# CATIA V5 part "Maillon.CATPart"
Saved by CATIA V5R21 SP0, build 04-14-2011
Part number: 0_274m_e14_1_028_0_12
Bounding box of the stored display mesh (mm): x -173.117 to -118.111, y -6 to 21, z 39.524 to 68.389
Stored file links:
  C:\TPO v2\SharedFS\Outgoing\0_274m_e14_1_028_0_12.CATPart

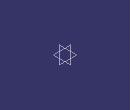
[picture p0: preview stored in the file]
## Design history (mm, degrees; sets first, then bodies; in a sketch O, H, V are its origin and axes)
AxisSystem1: origin (0, 0, 0), X (1, 0, 0), Y (0, 1, 0), Z (0, 0, 1)
Body1 "0_274m_e14_1_028_0_12" (main body)
  Solid1: solid without history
